VERSION 5.7 ;
BUSBITCHARS "[]" ;
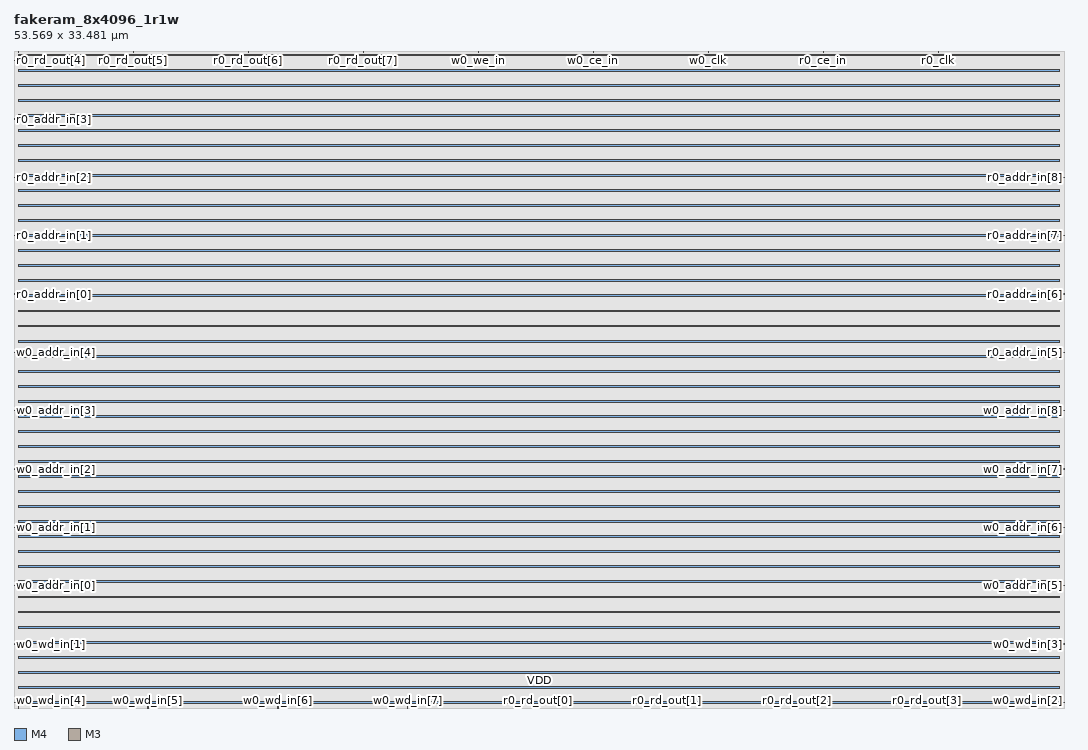
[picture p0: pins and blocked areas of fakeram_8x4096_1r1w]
MACRO fakeram_8x4096_1r1w
  FOREIGN fakeram_8x4096_1r1w 0 0 ;
  SYMMETRY X Y R90 ;
  SIZE 53.569 BY 33.481 ;
  CLASS BLOCK ;
  PIN w0_wd_in[0]
    DIRECTION INPUT ;
    USE SIGNAL ;
    SHAPE ABUTMENT ;
    PORT
      LAYER M4 ;
      RECT 0.000 0.276 0.072 0.300 ;
    END
  END w0_wd_in[0]
  PIN w0_wd_in[1]
    DIRECTION INPUT ;
    USE SIGNAL ;
    SHAPE ABUTMENT ;
    PORT
      LAYER M4 ;
      RECT 0.000 3.252 0.072 3.276 ;
    END
  END w0_wd_in[1]
  PIN w0_wd_in[2]
    DIRECTION INPUT ;
    USE SIGNAL ;
    SHAPE ABUTMENT ;
    PORT
      LAYER M4 ;
      RECT 53.497 0.276 53.569 0.300 ;
    END
  END w0_wd_in[2]
  PIN w0_wd_in[3]
    DIRECTION INPUT ;
    USE SIGNAL ;
    SHAPE ABUTMENT ;
    PORT
      LAYER M4 ;
      RECT 53.497 3.252 53.569 3.276 ;
    END
  END w0_wd_in[3]
  PIN w0_wd_in[4]
    DIRECTION INPUT ;
    USE SIGNAL ;
    SHAPE ABUTMENT ;
    PORT
      LAYER M3 ;
      RECT 0.207 0.000 0.225 0.054 ;
    END
  END w0_wd_in[4]
  PIN w0_wd_in[5]
    DIRECTION INPUT ;
    USE SIGNAL ;
    SHAPE ABUTMENT ;
    PORT
      LAYER M3 ;
      RECT 6.831 0.000 6.849 0.054 ;
    END
  END w0_wd_in[5]
  PIN w0_wd_in[6]
    DIRECTION INPUT ;
    USE SIGNAL ;
    SHAPE ABUTMENT ;
    PORT
      LAYER M3 ;
      RECT 13.455 0.000 13.473 0.054 ;
    END
  END w0_wd_in[6]
  PIN w0_wd_in[7]
    DIRECTION INPUT ;
    USE SIGNAL ;
    SHAPE ABUTMENT ;
    PORT
      LAYER M3 ;
      RECT 20.079 0.000 20.097 0.054 ;
    END
  END w0_wd_in[7]
  PIN r0_rd_out[0]
    DIRECTION OUTPUT ;
    USE SIGNAL ;
    SHAPE ABUTMENT ;
    PORT
      LAYER M3 ;
      RECT 26.703 0.000 26.721 0.054 ;
    END
  END r0_rd_out[0]
  PIN r0_rd_out[1]
    DIRECTION OUTPUT ;
    USE SIGNAL ;
    SHAPE ABUTMENT ;
    PORT
      LAYER M3 ;
      RECT 33.327 0.000 33.345 0.054 ;
    END
  END r0_rd_out[1]
  PIN r0_rd_out[2]
    DIRECTION OUTPUT ;
    USE SIGNAL ;
    SHAPE ABUTMENT ;
    PORT
      LAYER M3 ;
      RECT 39.951 0.000 39.969 0.054 ;
    END
  END r0_rd_out[2]
  PIN r0_rd_out[3]
    DIRECTION OUTPUT ;
    USE SIGNAL ;
    SHAPE ABUTMENT ;
    PORT
      LAYER M3 ;
      RECT 46.575 0.000 46.593 0.054 ;
    END
  END r0_rd_out[3]
  PIN r0_rd_out[4]
    DIRECTION OUTPUT ;
    USE SIGNAL ;
    SHAPE ABUTMENT ;
    PORT
      LAYER M3 ;
      RECT 0.207 33.427 0.225 33.481 ;
    END
  END r0_rd_out[4]
  PIN r0_rd_out[5]
    DIRECTION OUTPUT ;
    USE SIGNAL ;
    SHAPE ABUTMENT ;
    PORT
      LAYER M3 ;
      RECT 6.075 33.427 6.093 33.481 ;
    END
  END r0_rd_out[5]
  PIN r0_rd_out[6]
    DIRECTION OUTPUT ;
    USE SIGNAL ;
    SHAPE ABUTMENT ;
    PORT
      LAYER M3 ;
      RECT 11.943 33.427 11.961 33.481 ;
    END
  END r0_rd_out[6]
  PIN r0_rd_out[7]
    DIRECTION OUTPUT ;
    USE SIGNAL ;
    SHAPE ABUTMENT ;
    PORT
      LAYER M3 ;
      RECT 17.811 33.427 17.829 33.481 ;
    END
  END r0_rd_out[7]
  PIN w0_addr_in[0]
    DIRECTION INPUT ;
    USE SIGNAL ;
    SHAPE ABUTMENT ;
    PORT
      LAYER M4 ;
      RECT 0.000 6.228 0.072 6.252 ;
    END
  END w0_addr_in[0]
  PIN w0_addr_in[1]
    DIRECTION INPUT ;
    USE SIGNAL ;
    SHAPE ABUTMENT ;
    PORT
      LAYER M4 ;
      RECT 0.000 9.204 0.072 9.228 ;
    END
  END w0_addr_in[1]
  PIN w0_addr_in[2]
    DIRECTION INPUT ;
    USE SIGNAL ;
    SHAPE ABUTMENT ;
    PORT
      LAYER M4 ;
      RECT 0.000 12.180 0.072 12.204 ;
    END
  END w0_addr_in[2]
  PIN w0_addr_in[3]
    DIRECTION INPUT ;
    USE SIGNAL ;
    SHAPE ABUTMENT ;
    PORT
      LAYER M4 ;
      RECT 0.000 15.156 0.072 15.180 ;
    END
  END w0_addr_in[3]
  PIN w0_addr_in[4]
    DIRECTION INPUT ;
    USE SIGNAL ;
    SHAPE ABUTMENT ;
    PORT
      LAYER M4 ;
      RECT 0.000 18.132 0.072 18.156 ;
    END
  END w0_addr_in[4]
  PIN w0_addr_in[5]
    DIRECTION INPUT ;
    USE SIGNAL ;
    SHAPE ABUTMENT ;
    PORT
      LAYER M4 ;
      RECT 53.497 6.228 53.569 6.252 ;
    END
  END w0_addr_in[5]
  PIN w0_addr_in[6]
    DIRECTION INPUT ;
    USE SIGNAL ;
    SHAPE ABUTMENT ;
    PORT
      LAYER M4 ;
      RECT 53.497 9.204 53.569 9.228 ;
    END
  END w0_addr_in[6]
  PIN w0_addr_in[7]
    DIRECTION INPUT ;
    USE SIGNAL ;
    SHAPE ABUTMENT ;
    PORT
      LAYER M4 ;
      RECT 53.497 12.180 53.569 12.204 ;
    END
  END w0_addr_in[7]
  PIN w0_addr_in[8]
    DIRECTION INPUT ;
    USE SIGNAL ;
    SHAPE ABUTMENT ;
    PORT
      LAYER M4 ;
      RECT 53.497 15.156 53.569 15.180 ;
    END
  END w0_addr_in[8]
  PIN r0_addr_in[0]
    DIRECTION INPUT ;
    USE SIGNAL ;
    SHAPE ABUTMENT ;
    PORT
      LAYER M4 ;
      RECT 0.000 21.108 0.072 21.132 ;
    END
  END r0_addr_in[0]
  PIN r0_addr_in[1]
    DIRECTION INPUT ;
    USE SIGNAL ;
    SHAPE ABUTMENT ;
    PORT
      LAYER M4 ;
      RECT 0.000 24.084 0.072 24.108 ;
    END
  END r0_addr_in[1]
  PIN r0_addr_in[2]
    DIRECTION INPUT ;
    USE SIGNAL ;
    SHAPE ABUTMENT ;
    PORT
      LAYER M4 ;
      RECT 0.000 27.060 0.072 27.084 ;
    END
  END r0_addr_in[2]
  PIN r0_addr_in[3]
    DIRECTION INPUT ;
    USE SIGNAL ;
    SHAPE ABUTMENT ;
    PORT
      LAYER M4 ;
      RECT 0.000 30.036 0.072 30.060 ;
    END
  END r0_addr_in[3]
  PIN r0_addr_in[4]
    DIRECTION INPUT ;
    USE SIGNAL ;
    SHAPE ABUTMENT ;
    PORT
      LAYER M4 ;
      RECT 0.000 33.012 0.072 33.036 ;
    END
  END r0_addr_in[4]
  PIN r0_addr_in[5]
    DIRECTION INPUT ;
    USE SIGNAL ;
    SHAPE ABUTMENT ;
    PORT
      LAYER M4 ;
      RECT 53.497 18.132 53.569 18.156 ;
    END
  END r0_addr_in[5]
  PIN r0_addr_in[6]
    DIRECTION INPUT ;
    USE SIGNAL ;
    SHAPE ABUTMENT ;
    PORT
      LAYER M4 ;
      RECT 53.497 21.108 53.569 21.132 ;
    END
  END r0_addr_in[6]
  PIN r0_addr_in[7]
    DIRECTION INPUT ;
    USE SIGNAL ;
    SHAPE ABUTMENT ;
    PORT
      LAYER M4 ;
      RECT 53.497 24.084 53.569 24.108 ;
    END
  END r0_addr_in[7]
  PIN r0_addr_in[8]
    DIRECTION INPUT ;
    USE SIGNAL ;
    SHAPE ABUTMENT ;
    PORT
      LAYER M4 ;
      RECT 53.497 27.060 53.569 27.084 ;
    END
  END r0_addr_in[8]
  PIN w0_we_in
    DIRECTION INPUT ;
    USE SIGNAL ;
    SHAPE ABUTMENT ;
    PORT
      LAYER M3 ;
      RECT 23.679 33.427 23.697 33.481 ;
    END
  END w0_we_in
  PIN w0_ce_in
    DIRECTION INPUT ;
    USE SIGNAL ;
    SHAPE ABUTMENT ;
    PORT
      LAYER M3 ;
      RECT 29.547 33.427 29.565 33.481 ;
    END
  END w0_ce_in
  PIN w0_clk
    DIRECTION INPUT ;
    USE SIGNAL ;
    SHAPE ABUTMENT ;
    PORT
      LAYER M3 ;
      RECT 35.415 33.427 35.433 33.481 ;
    END
  END w0_clk
  PIN r0_ce_in
    DIRECTION INPUT ;
    USE SIGNAL ;
    SHAPE ABUTMENT ;
    PORT
      LAYER M3 ;
      RECT 41.283 33.427 41.301 33.481 ;
    END
  END r0_ce_in
  PIN r0_clk
    DIRECTION INPUT ;
    USE SIGNAL ;
    SHAPE ABUTMENT ;
    PORT
      LAYER M3 ;
      RECT 47.151 33.427 47.169 33.481 ;
    END
  END r0_clk
  PIN VSS
    DIRECTION INOUT ;
    USE GROUND ;
    PORT
      LAYER M4 ;
      RECT 0.216 0.240 53.353 0.336 ;
      RECT 0.216 1.008 53.353 1.104 ;
      RECT 0.216 1.776 53.353 1.872 ;
      RECT 0.216 2.544 53.353 2.640 ;
      RECT 0.216 3.312 53.353 3.408 ;
      RECT 0.216 4.080 53.353 4.176 ;
      RECT 0.216 4.848 53.353 4.944 ;
      RECT 0.216 5.616 53.353 5.712 ;
      RECT 0.216 6.384 53.353 6.480 ;
      RECT 0.216 7.152 53.353 7.248 ;
      RECT 0.216 7.920 53.353 8.016 ;
      RECT 0.216 8.688 53.353 8.784 ;
      RECT 0.216 9.456 53.353 9.552 ;
      RECT 0.216 10.224 53.353 10.320 ;
      RECT 0.216 10.992 53.353 11.088 ;
      RECT 0.216 11.760 53.353 11.856 ;
      RECT 0.216 12.528 53.353 12.624 ;
      RECT 0.216 13.296 53.353 13.392 ;
      RECT 0.216 14.064 53.353 14.160 ;
      RECT 0.216 14.832 53.353 14.928 ;
      RECT 0.216 15.600 53.353 15.696 ;
      RECT 0.216 16.368 53.353 16.464 ;
      RECT 0.216 17.136 53.353 17.232 ;
      RECT 0.216 17.904 53.353 18.000 ;
      RECT 0.216 18.672 53.353 18.768 ;
      RECT 0.216 19.440 53.353 19.536 ;
      RECT 0.216 20.208 53.353 20.304 ;
      RECT 0.216 20.976 53.353 21.072 ;
      RECT 0.216 21.744 53.353 21.840 ;
      RECT 0.216 22.512 53.353 22.608 ;
      RECT 0.216 23.280 53.353 23.376 ;
      RECT 0.216 24.048 53.353 24.144 ;
      RECT 0.216 24.816 53.353 24.912 ;
      RECT 0.216 25.584 53.353 25.680 ;
      RECT 0.216 26.352 53.353 26.448 ;
      RECT 0.216 27.120 53.353 27.216 ;
      RECT 0.216 27.888 53.353 27.984 ;
      RECT 0.216 28.656 53.353 28.752 ;
      RECT 0.216 29.424 53.353 29.520 ;
      RECT 0.216 30.192 53.353 30.288 ;
      RECT 0.216 30.960 53.353 31.056 ;
      RECT 0.216 31.728 53.353 31.824 ;
      RECT 0.216 32.496 53.353 32.592 ;
      RECT 0.216 33.264 53.353 33.360 ;
    END
  END VSS
  PIN VDD
    DIRECTION INOUT ;
    USE POWER ;
    PORT
      LAYER M4 ;
      RECT 0.216 0.240 53.353 0.336 ;
      RECT 0.216 1.008 53.353 1.104 ;
      RECT 0.216 1.776 53.353 1.872 ;
      RECT 0.216 2.544 53.353 2.640 ;
      RECT 0.216 3.312 53.353 3.408 ;
      RECT 0.216 4.080 53.353 4.176 ;
      RECT 0.216 4.848 53.353 4.944 ;
      RECT 0.216 5.616 53.353 5.712 ;
      RECT 0.216 6.384 53.353 6.480 ;
      RECT 0.216 7.152 53.353 7.248 ;
      RECT 0.216 7.920 53.353 8.016 ;
      RECT 0.216 8.688 53.353 8.784 ;
      RECT 0.216 9.456 53.353 9.552 ;
      RECT 0.216 10.224 53.353 10.320 ;
      RECT 0.216 10.992 53.353 11.088 ;
      RECT 0.216 11.760 53.353 11.856 ;
      RECT 0.216 12.528 53.353 12.624 ;
      RECT 0.216 13.296 53.353 13.392 ;
      RECT 0.216 14.064 53.353 14.160 ;
      RECT 0.216 14.832 53.353 14.928 ;
      RECT 0.216 15.600 53.353 15.696 ;
      RECT 0.216 16.368 53.353 16.464 ;
      RECT 0.216 17.136 53.353 17.232 ;
      RECT 0.216 17.904 53.353 18.000 ;
      RECT 0.216 18.672 53.353 18.768 ;
      RECT 0.216 19.440 53.353 19.536 ;
      RECT 0.216 20.208 53.353 20.304 ;
      RECT 0.216 20.976 53.353 21.072 ;
      RECT 0.216 21.744 53.353 21.840 ;
      RECT 0.216 22.512 53.353 22.608 ;
      RECT 0.216 23.280 53.353 23.376 ;
      RECT 0.216 24.048 53.353 24.144 ;
      RECT 0.216 24.816 53.353 24.912 ;
      RECT 0.216 25.584 53.353 25.680 ;
      RECT 0.216 26.352 53.353 26.448 ;
      RECT 0.216 27.120 53.353 27.216 ;
      RECT 0.216 27.888 53.353 27.984 ;
      RECT 0.216 28.656 53.353 28.752 ;
      RECT 0.216 29.424 53.353 29.520 ;
      RECT 0.216 30.192 53.353 30.288 ;
      RECT 0.216 30.960 53.353 31.056 ;
      RECT 0.216 31.728 53.353 31.824 ;
      RECT 0.216 32.496 53.353 32.592 ;
      RECT 0.216 33.264 53.353 33.360 ;
    END
  END VDD
  OBS
    LAYER M1 ;
    RECT 0 0 53.569 33.481 ;
    LAYER M2 ;
    RECT 0 0 53.569 33.481 ;
    LAYER M3 ;
    RECT 0 0 53.569 33.481 ;
    LAYER M4 ;
    RECT 0 0 53.569 33.481 ;
  END
END fakeram_8x4096_1r1w

END LIBRARY
